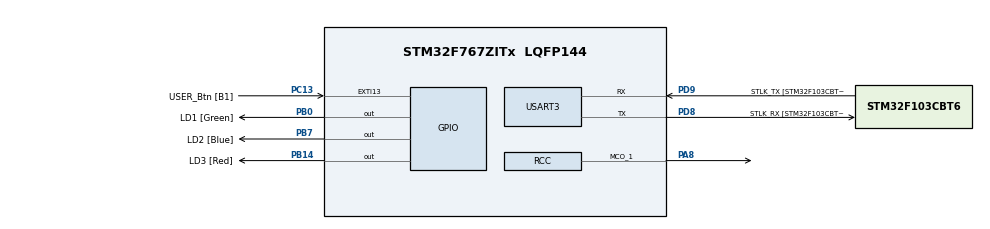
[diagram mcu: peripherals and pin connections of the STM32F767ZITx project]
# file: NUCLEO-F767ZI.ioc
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ADC1.Channel-16\#ChannelRegularConversion=ADC_CHANNEL_TEMPSENSOR
ADC1.Channel-17\#ChannelRegularConversion=ADC_CHANNEL_TEMPSENSOR
ADC1.Channel-18\#ChannelRegularConversion=ADC_CHANNEL_TEMPSENSOR
ADC1.Channel-19\#ChannelRegularConversion=ADC_CHANNEL_TEMPSENSOR
ADC1.Channel-20\#ChannelRegularConversion=ADC_CHANNEL_TEMPSENSOR
ADC1.Channel-21\#ChannelRegularConversion=ADC_CHANNEL_TEMPSENSOR
ADC1.Channel-22\#ChannelRegularConversion=ADC_CHANNEL_TEMPSENSOR
ADC1.Channel-23\#ChannelRegularConversion=ADC_CHANNEL_TEMPSENSOR
ADC1.Channel-24\#ChannelRegularConversion=ADC_CHANNEL_TEMPSENSOR
ADC1.Channel-25\#ChannelRegularConversion=ADC_CHANNEL_TEMPSENSOR
ADC1.Channel-26\#ChannelRegularConversion=ADC_CHANNEL_TEMPSENSOR
ADC1.Channel-27\#ChannelRegularConversion=ADC_CHANNEL_TEMPSENSOR
ADC1.Channel-28\#ChannelRegularConversion=ADC_CHANNEL_TEMPSENSOR
ADC1.Channel-29\#ChannelRegularConversion=ADC_CHANNEL_TEMPSENSOR
ADC1.Channel-30\#ChannelRegularConversion=ADC_CHANNEL_TEMPSENSOR
ADC1.Channel-31\#ChannelRegularConversion=ADC_CHANNEL_TEMPSENSOR
ADC1.ContinuousConvMode=ENABLE
ADC1.DMAContinuousRequests=ENABLE
ADC1.NbrOfConversion=16
ADC1.NbrOfConversionFlag=1
ADC1.Rank-16\#ChannelRegularConversion=1
ADC1.Rank-17\#ChannelRegularConversion=2
ADC1.Rank-18\#ChannelRegularConversion=3
ADC1.Rank-19\#ChannelRegularConversion=4
ADC1.Rank-20\#ChannelRegularConversion=5
ADC1.Rank-21\#ChannelRegularConversion=6
ADC1.Rank-22\#ChannelRegularConversion=7
ADC1.Rank-23\#ChannelRegularConversion=8
ADC1.Rank-24\#ChannelRegularConversion=9
ADC1.Rank-25\#ChannelRegularConversion=10
ADC1.Rank-26\#ChannelRegularConversion=11
ADC1.Rank-27\#ChannelRegularConversion=12
ADC1.Rank-28\#ChannelRegularConversion=13
ADC1.Rank-29\#ChannelRegularConversion=14
ADC1.Rank-30\#ChannelRegularConversion=15
ADC1.Rank-31\#ChannelRegularConversion=16
ADC1.SamplingTime-16\#ChannelRegularConversion=ADC_SAMPLETIME_3CYCLES
ADC1.SamplingTime-17\#ChannelRegularConversion=ADC_SAMPLETIME_3CYCLES
ADC1.SamplingTime-18\#ChannelRegularConversion=ADC_SAMPLETIME_3CYCLES
ADC1.SamplingTime-19\#ChannelRegularConversion=ADC_SAMPLETIME_3CYCLES
ADC1.SamplingTime-20\#ChannelRegularConversion=ADC_SAMPLETIME_3CYCLES
ADC1.SamplingTime-21\#ChannelRegularConversion=ADC_SAMPLETIME_3CYCLES
ADC1.SamplingTime-22\#ChannelRegularConversion=ADC_SAMPLETIME_3CYCLES
ADC1.SamplingTime-23\#ChannelRegularConversion=ADC_SAMPLETIME_3CYCLES
ADC1.SamplingTime-24\#ChannelRegularConversion=ADC_SAMPLETIME_3CYCLES
ADC1.SamplingTime-25\#ChannelRegularConversion=ADC_SAMPLETIME_3CYCLES
ADC1.SamplingTime-26\#ChannelRegularConversion=ADC_SAMPLETIME_3CYCLES
ADC1.SamplingTime-27\#ChannelRegularConversion=ADC_SAMPLETIME_3CYCLES
ADC1.SamplingTime-28\#ChannelRegularConversion=ADC_SAMPLETIME_3CYCLES
ADC1.SamplingTime-29\#ChannelRegularConversion=ADC_SAMPLETIME_3CYCLES
ADC1.SamplingTime-30\#ChannelRegularConversion=ADC_SAMPLETIME_3CYCLES
ADC1.SamplingTime-31\#ChannelRegularConversion=ADC_SAMPLETIME_3CYCLES
ADC1.master=1
Dma.ADC1.0.Direction=DMA_PERIPH_TO_MEMORY
Dma.ADC1.0.FIFOMode=DMA_FIFOMODE_ENABLE
Dma.ADC1.0.FIFOThreshold=DMA_FIFO_THRESHOLD_FULL
Dma.ADC1.0.Instance=DMA2_Stream4
Dma.ADC1.0.MemBurst=DMA_MBURST_SINGLE
Dma.ADC1.0.MemDataAlignment=DMA_MDATAALIGN_HALFWORD
Dma.ADC1.0.MemInc=DMA_MINC_ENABLE
Dma.ADC1.0.Mode=DMA_NORMAL
Dma.ADC1.0.PeriphBurst=DMA_PBURST_SINGLE
Dma.ADC1.0.PeriphDataAlignment=DMA_PDATAALIGN_HALFWORD
Dma.ADC1.0.PeriphInc=DMA_PINC_DISABLE
Dma.ADC1.0.Priority=DMA_PRIORITY_LOW
Dma.Request0=ADC1
Mcu.Family=STM32F7
Mcu.Name=STM32F767ZITx
Mcu.Package=LQFP144
NVIC.DMA2_Stream4_IRQn=true\:0\:0\:false\:false\:true\:false\:true
NVIC.EXTI15_10_IRQn=true\:0\:0\:false\:false\:true\:true\:true
NVIC.PriorityGroup=NVIC_PRIORITYGROUP_4
PA13.GPIO_Label=TMS
PA13.Mode=Serial_Wire
PA13.Signal=SYS_JTMS-SWDIO
PA14.GPIO_Label=TCK
PA14.Mode=Serial_Wire
PA14.Signal=SYS_JTCK-SWCLK
PA8.Mode=Clock-out-1
PA8.Signal=RCC_MCO_1
PB0.GPIO_Label=LD1 [Green]
PB0.Signal=GPIO_Output
PB14.GPIO_Label=LD3 [Red]
PB14.Signal=GPIO_Output
PB3.GPIO_Label=SWO
PB3.Signal=SYS_JTDO-SWO
PB7.GPIO_Label=LD2 [Blue]
PB7.Signal=GPIO_Output
PC13.GPIO_Label=USER_Btn [B1]
PC13.Signal=GPXTI13
PC14/OSC32_IN.Mode=LSE-External-Oscillator
PC14/OSC32_IN.Signal=RCC_OSC32_IN
PC15/OSC32_OUT.Mode=LSE-External-Oscillator
PC15/OSC32_OUT.Signal=RCC_OSC32_OUT
PD8.GPIO_Label=STLK_RX [STM32F103CBT6_PA3]
PD8.Mode=Asynchronous
PD8.Signal=USART3_TX
PD9.GPIO_Label=STLK_TX [STM32F103CBT6_PA2]
PD9.Mode=Asynchronous
PD9.Signal=USART3_RX
PH0/OSC_IN.Signal=RCC_OSC_IN
ProjectManager.HeapSize=0x200
ProjectManager.StackSize=0x400
ProjectManager.TargetToolchain=STM32CubeIDE
RCC.48MHZClocksFreq_Value=24000000
RCC.AHBFreq_Value=84000000
RCC.APB1CLKDivider=RCC_HCLK_DIV2
RCC.APB1Freq_Value=42000000
RCC.APB1TimFreq_Value=84000000
RCC.APB2Freq_Value=84000000
RCC.APB2TimFreq_Value=84000000
RCC.CortexFreq_Value=84000000
RCC.HCLKFreq_Value=84000000
RCC.HSE_VALUE=8000000
RCC.HSI_VALUE=16000000
RCC.PLLM=8
RCC.PLLMUL=RCC_PLL_MUL9
RCC.PLLN=168
RCC.PLLP=RCC_PLLP_DIV4
RCC.PLLQ=4
RCC.PRESCALERUSB=RCC_USBCLKSOURCE_PLL_DIV1_5
RCC.RCC_MCO1Source=RCC_MCO1SOURCE_LSE
RCC.SYSCLKFreq_VALUE=84000000
RCC.SYSCLKSource=RCC_SYSCLKSOURCE_PLLCLK
RCC.SYSCLKSourceVirtual=RCC_SYSCLKSOURCE_PLLCLK
RCC.USBFreq_Value=84000000
RCC.VCOOutputFreq_Value=336000000
USART3.VirtualMode-Asynchronous=VM_ASYNC
VP_ADC1_TempSens_Input.Mode=IN-TempSens
VP_TIM6_VS_ClockSourceINT.Mode=Enable_Timer
board=NUCLEO-F767ZI

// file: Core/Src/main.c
/* USER CODE BEGIN Header */
/**
  ******************************************************************************
  * @file           : main.c
  * @brief          : Main program body
  ******************************************************************************
  * @attention
  *
  * Copyright (c) 2022 STMicroelectronics.
  * All rights reserved.
  *
  * This software is licensed under terms that can be found in the LICENSE file
  * in the root directory of this software component.
  * If no LICENSE file comes with this software, it is provided AS-IS.
  *
  ******************************************************************************
  */
/* USER CODE END Header */
#include "main.h"

ADC_HandleTypeDef hadc1;

TIM_HandleTypeDef htim6;

UART_HandleTypeDef huart3;

void SystemClock_Config(void);
static void MX_GPIO_Init(void);
static void MX_USART3_UART_Init(void);
static void MX_TIM6_Init(void);
static void MX_ADC1_Init(void);

int main(void)
{

  /* MCU Configuration--------------------------------------------------------*/

  /* Reset of all peripherals, Initializes the Flash interface and the Systick. */
  HAL_Init();

  /* Configure the system clock */
  SystemClock_Config();

  /* Initialize all configured peripherals */
  MX_GPIO_Init();
  MX_USART3_UART_Init();
  MX_TIM6_Init();
  MX_ADC1_Init();

  /* Infinite loop */
  while (1)
  {

  }
}

void SystemClock_Config(void)
{
  RCC_OscInitTypeDef RCC_OscInitStruct = {0};
  RCC_ClkInitTypeDef RCC_ClkInitStruct = {0};

  /** Configure LSE Drive Capability
  */
  HAL_PWR_EnableBkUpAccess();
  __HAL_RCC_LSEDRIVE_CONFIG(RCC_LSEDRIVE_LOW);
  /** Configure the main internal regulator output voltage
  */
  __HAL_RCC_PWR_CLK_ENABLE();
  __HAL_PWR_VOLTAGESCALING_CONFIG(PWR_REGULATOR_VOLTAGE_SCALE3);
  /** Initializes the RCC Oscillators according to the specified parameters
  * in the RCC_OscInitTypeDef structure.
  */
  RCC_OscInitStruct.OscillatorType = RCC_OSCILLATORTYPE_HSI|RCC_OSCILLATORTYPE_LSE;
  RCC_OscInitStruct.LSEState = RCC_LSE_ON;
  RCC_OscInitStruct.HSIState = RCC_HSI_ON;
  RCC_OscInitStruct.HSICalibrationValue = RCC_HSICALIBRATION_DEFAULT;
  RCC_OscInitStruct.PLL.PLLState = RCC_PLL_NONE;
  if (HAL_RCC_OscConfig(&RCC_OscInitStruct) != HAL_OK)
  {
    Error_Handler();
  }
  /** Initializes the CPU, AHB and APB buses clocks
  */
  RCC_ClkInitStruct.ClockType = RCC_CLOCKTYPE_HCLK|RCC_CLOCKTYPE_SYSCLK
                              |RCC_CLOCKTYPE_PCLK1|RCC_CLOCKTYPE_PCLK2;
  RCC_ClkInitStruct.SYSCLKSource = RCC_SYSCLKSOURCE_HSI;
  RCC_ClkInitStruct.AHBCLKDivider = RCC_SYSCLK_DIV1;
  RCC_ClkInitStruct.APB1CLKDivider = RCC_HCLK_DIV1;
  RCC_ClkInitStruct.APB2CLKDivider = RCC_HCLK_DIV1;

  if (HAL_RCC_ClockConfig(&RCC_ClkInitStruct, FLASH_LATENCY_0) != HAL_OK)
  {
    Error_Handler();
  }
  HAL_RCC_MCOConfig(RCC_MCO1, RCC_MCO1SOURCE_LSE, RCC_MCODIV_1);
}

static void MX_ADC1_Init(void)
{

  ADC_ChannelConfTypeDef sConfig = {0};

  /** Configure the global features of the ADC (Clock, Resolution, Data Alignment and number of conversion)
  */
  hadc1.Instance = ADC1;
  hadc1.Init.ClockPrescaler = ADC_CLOCK_SYNC_PCLK_DIV2;
  hadc1.Init.Resolution = ADC_RESOLUTION_12B;
  hadc1.Init.ScanConvMode = ADC_SCAN_DISABLE;
  hadc1.Init.ContinuousConvMode = DISABLE;
  hadc1.Init.DiscontinuousConvMode = DISABLE;
  hadc1.Init.ExternalTrigConvEdge = ADC_EXTERNALTRIGCONVEDGE_NONE;
  hadc1.Init.ExternalTrigConv = ADC_SOFTWARE_START;
  hadc1.Init.DataAlign = ADC_DATAALIGN_RIGHT;
  hadc1.Init.NbrOfConversion = 1;
  hadc1.Init.DMAContinuousRequests = DISABLE;
  hadc1.Init.EOCSelection = ADC_EOC_SINGLE_CONV;
  if (HAL_ADC_Init(&hadc1) != HAL_OK)
  {
    Error_Handler();
  }
  /** Configure for the selected ADC regular channel its corresponding rank in the sequencer and its sample time.
  */
  sConfig.Channel = ADC_CHANNEL_3;
  sConfig.Rank = ADC_REGULAR_RANK_1;
  sConfig.SamplingTime = ADC_SAMPLETIME_3CYCLES;
  if (HAL_ADC_ConfigChannel(&hadc1, &sConfig) != HAL_OK)
  {
    Error_Handler();
  }

}

static void MX_TIM6_Init(void)
{

  TIM_MasterConfigTypeDef sMasterConfig = {0};

  htim6.Instance = TIM6;
  htim6.Init.Prescaler = 0;
  htim6.Init.CounterMode = TIM_COUNTERMODE_UP;
  htim6.Init.Period = 65535;
  htim6.Init.AutoReloadPreload = TIM_AUTORELOAD_PRELOAD_DISABLE;
  if (HAL_TIM_Base_Init(&htim6) != HAL_OK)
  {
    Error_Handler();
  }
  sMasterConfig.MasterOutputTrigger = TIM_TRGO_RESET;
  sMasterConfig.MasterSlaveMode = TIM_MASTERSLAVEMODE_DISABLE;
  if (HAL_TIMEx_MasterConfigSynchronization(&htim6, &sMasterConfig) != HAL_OK)
  {
    Error_Handler();
  }

}

static void MX_USART3_UART_Init(void)
{

  huart3.Instance = USART3;
  huart3.Init.BaudRate = 115200;
  huart3.Init.WordLength = UART_WORDLENGTH_8B;
  huart3.Init.StopBits = UART_STOPBITS_1;
  huart3.Init.Parity = UART_PARITY_NONE;
  huart3.Init.Mode = UART_MODE_TX_RX;
  huart3.Init.HwFlowCtl = UART_HWCONTROL_NONE;
  huart3.Init.OverSampling = UART_OVERSAMPLING_16;
  huart3.Init.OneBitSampling = UART_ONE_BIT_SAMPLE_DISABLE;
  huart3.AdvancedInit.AdvFeatureInit = UART_ADVFEATURE_NO_INIT;
  if (HAL_UART_Init(&huart3) != HAL_OK)
  {
    Error_Handler();
  }

}

static void MX_GPIO_Init(void)
{
  GPIO_InitTypeDef GPIO_InitStruct = {0};

  /* GPIO Ports Clock Enable */
  __HAL_RCC_GPIOC_CLK_ENABLE();
  __HAL_RCC_GPIOH_CLK_ENABLE();
  __HAL_RCC_GPIOA_CLK_ENABLE();
  __HAL_RCC_GPIOB_CLK_ENABLE();
  __HAL_RCC_GPIOD_CLK_ENABLE();

  /*Configure GPIO pin Output Level */
  HAL_GPIO_WritePin(GPIOB, LD1_Pin|LD3_Pin|LD2_Pin, GPIO_PIN_RESET);

  /*Configure GPIO pin : USER_Btn_Pin */
  GPIO_InitStruct.Pin = USER_Btn_Pin;
  GPIO_InitStruct.Mode = GPIO_MODE_IT_RISING;
  GPIO_InitStruct.Pull = GPIO_NOPULL;
  HAL_GPIO_Init(USER_Btn_GPIO_Port, &GPIO_InitStruct);

  /*Configure GPIO pins : LD1_Pin LD3_Pin LD2_Pin */
  GPIO_InitStruct.Pin = LD1_Pin|LD3_Pin|LD2_Pin;
  GPIO_InitStruct.Mode = GPIO_MODE_OUTPUT_PP;
  GPIO_InitStruct.Pull = GPIO_NOPULL;
  GPIO_InitStruct.Speed = GPIO_SPEED_FREQ_LOW;
  HAL_GPIO_Init(GPIOB, &GPIO_InitStruct);

  /*Configure GPIO pin : PA8 */
  GPIO_InitStruct.Pin = GPIO_PIN_8;
  GPIO_InitStruct.Mode = GPIO_MODE_AF_PP;
  GPIO_InitStruct.Pull = GPIO_NOPULL;
  GPIO_InitStruct.Speed = GPIO_SPEED_FREQ_LOW;
  GPIO_InitStruct.Alternate = GPIO_AF0_MCO;
  HAL_GPIO_Init(GPIOA, &GPIO_InitStruct);

}

void Error_Handler(void)
{
  __disable_irq();
  while (1)
  {
  }
}
